VERSION 5.7 ;
BUSBITCHARS "[]" ;
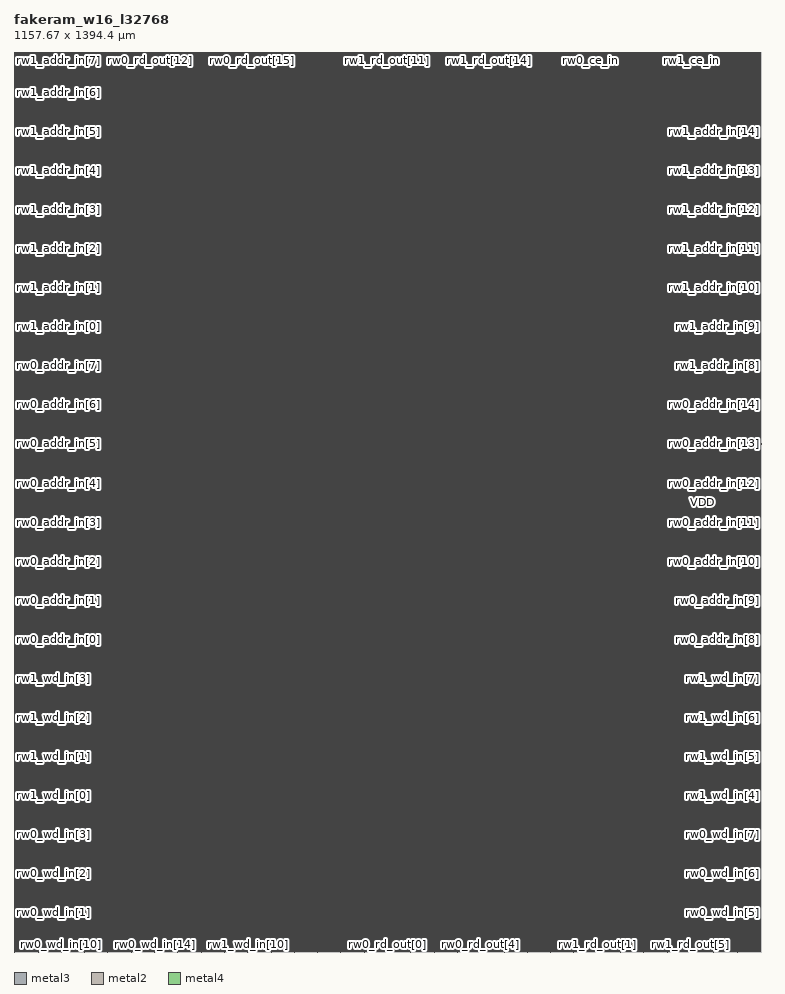
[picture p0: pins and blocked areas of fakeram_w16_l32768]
MACRO fakeram_w16_l32768
  FOREIGN fakeram_w16_l32768 0 0 ;
  SYMMETRY X Y R90 ;
  SIZE 1157.670 BY 1394.400 ;
  CLASS BLOCK ;
  PIN rw0_wd_in[0]
    DIRECTION INPUT ;
    USE SIGNAL ;
    SHAPE ABUTMENT ;
    PORT
      LAYER metal3 ;
      RECT 0.000 0.805 0.210 0.875 ;
    END
  END rw0_wd_in[0]
  PIN rw0_wd_in[1]
    DIRECTION INPUT ;
    USE SIGNAL ;
    SHAPE ABUTMENT ;
    PORT
      LAYER metal3 ;
      RECT 0.000 61.285 0.210 61.355 ;
    END
  END rw0_wd_in[1]
  PIN rw0_wd_in[2]
    DIRECTION INPUT ;
    USE SIGNAL ;
    SHAPE ABUTMENT ;
    PORT
      LAYER metal3 ;
      RECT 0.000 121.765 0.210 121.835 ;
    END
  END rw0_wd_in[2]
  PIN rw0_wd_in[3]
    DIRECTION INPUT ;
    USE SIGNAL ;
    SHAPE ABUTMENT ;
    PORT
      LAYER metal3 ;
      RECT 0.000 182.245 0.210 182.315 ;
    END
  END rw0_wd_in[3]
  PIN rw0_wd_in[4]
    DIRECTION INPUT ;
    USE SIGNAL ;
    SHAPE ABUTMENT ;
    PORT
      LAYER metal3 ;
      RECT 1157.460 0.805 1157.670 0.875 ;
    END
  END rw0_wd_in[4]
  PIN rw0_wd_in[5]
    DIRECTION INPUT ;
    USE SIGNAL ;
    SHAPE ABUTMENT ;
    PORT
      LAYER metal3 ;
      RECT 1157.460 61.285 1157.670 61.355 ;
    END
  END rw0_wd_in[5]
  PIN rw0_wd_in[6]
    DIRECTION INPUT ;
    USE SIGNAL ;
    SHAPE ABUTMENT ;
    PORT
      LAYER metal3 ;
      RECT 1157.460 121.765 1157.670 121.835 ;
    END
  END rw0_wd_in[6]
  PIN rw0_wd_in[7]
    DIRECTION INPUT ;
    USE SIGNAL ;
    SHAPE ABUTMENT ;
    PORT
      LAYER metal3 ;
      RECT 1157.460 182.245 1157.670 182.315 ;
    END
  END rw0_wd_in[7]
  PIN rw0_wd_in[8]
    DIRECTION INPUT ;
    USE SIGNAL ;
    SHAPE ABUTMENT ;
    PORT
      LAYER metal2 ;
      RECT 1.105 0.000 1.175 0.210 ;
    END
  END rw0_wd_in[8]
  PIN rw0_wd_in[9]
    DIRECTION INPUT ;
    USE SIGNAL ;
    SHAPE ABUTMENT ;
    PORT
      LAYER metal2 ;
      RECT 37.205 0.000 37.275 0.210 ;
    END
  END rw0_wd_in[9]
  PIN rw0_wd_in[10]
    DIRECTION INPUT ;
    USE SIGNAL ;
    SHAPE ABUTMENT ;
    PORT
      LAYER metal2 ;
      RECT 73.305 0.000 73.375 0.210 ;
    END
  END rw0_wd_in[10]
  PIN rw0_wd_in[11]
    DIRECTION INPUT ;
    USE SIGNAL ;
    SHAPE ABUTMENT ;
    PORT
      LAYER metal2 ;
      RECT 109.405 0.000 109.475 0.210 ;
    END
  END rw0_wd_in[11]
  PIN rw0_wd_in[12]
    DIRECTION INPUT ;
    USE SIGNAL ;
    SHAPE ABUTMENT ;
    PORT
      LAYER metal2 ;
      RECT 145.505 0.000 145.575 0.210 ;
    END
  END rw0_wd_in[12]
  PIN rw0_wd_in[13]
    DIRECTION INPUT ;
    USE SIGNAL ;
    SHAPE ABUTMENT ;
    PORT
      LAYER metal2 ;
      RECT 181.605 0.000 181.675 0.210 ;
    END
  END rw0_wd_in[13]
  PIN rw0_wd_in[14]
    DIRECTION INPUT ;
    USE SIGNAL ;
    SHAPE ABUTMENT ;
    PORT
      LAYER metal2 ;
      RECT 217.705 0.000 217.775 0.210 ;
    END
  END rw0_wd_in[14]
  PIN rw0_wd_in[15]
    DIRECTION INPUT ;
    USE SIGNAL ;
    SHAPE ABUTMENT ;
    PORT
      LAYER metal2 ;
      RECT 253.805 0.000 253.875 0.210 ;
    END
  END rw0_wd_in[15]
  PIN rw1_wd_in[0]
    DIRECTION INPUT ;
    USE SIGNAL ;
    SHAPE ABUTMENT ;
    PORT
      LAYER metal3 ;
      RECT 0.000 242.725 0.210 242.795 ;
    END
  END rw1_wd_in[0]
  PIN rw1_wd_in[1]
    DIRECTION INPUT ;
    USE SIGNAL ;
    SHAPE ABUTMENT ;
    PORT
      LAYER metal3 ;
      RECT 0.000 303.205 0.210 303.275 ;
    END
  END rw1_wd_in[1]
  PIN rw1_wd_in[2]
    DIRECTION INPUT ;
    USE SIGNAL ;
    SHAPE ABUTMENT ;
    PORT
      LAYER metal3 ;
      RECT 0.000 363.685 0.210 363.755 ;
    END
  END rw1_wd_in[2]
  PIN rw1_wd_in[3]
    DIRECTION INPUT ;
    USE SIGNAL ;
    SHAPE ABUTMENT ;
    PORT
      LAYER metal3 ;
      RECT 0.000 424.165 0.210 424.235 ;
    END
  END rw1_wd_in[3]
  PIN rw1_wd_in[4]
    DIRECTION INPUT ;
    USE SIGNAL ;
    SHAPE ABUTMENT ;
    PORT
      LAYER metal3 ;
      RECT 1157.460 242.725 1157.670 242.795 ;
    END
  END rw1_wd_in[4]
  PIN rw1_wd_in[5]
    DIRECTION INPUT ;
    USE SIGNAL ;
    SHAPE ABUTMENT ;
    PORT
      LAYER metal3 ;
      RECT 1157.460 303.205 1157.670 303.275 ;
    END
  END rw1_wd_in[5]
  PIN rw1_wd_in[6]
    DIRECTION INPUT ;
    USE SIGNAL ;
    SHAPE ABUTMENT ;
    PORT
      LAYER metal3 ;
      RECT 1157.460 363.685 1157.670 363.755 ;
    END
  END rw1_wd_in[6]
  PIN rw1_wd_in[7]
    DIRECTION INPUT ;
    USE SIGNAL ;
    SHAPE ABUTMENT ;
    PORT
      LAYER metal3 ;
      RECT 1157.460 424.165 1157.670 424.235 ;
    END
  END rw1_wd_in[7]
  PIN rw1_wd_in[8]
    DIRECTION INPUT ;
    USE SIGNAL ;
    SHAPE ABUTMENT ;
    PORT
      LAYER metal2 ;
      RECT 289.905 0.000 289.975 0.210 ;
    END
  END rw1_wd_in[8]
  PIN rw1_wd_in[9]
    DIRECTION INPUT ;
    USE SIGNAL ;
    SHAPE ABUTMENT ;
    PORT
      LAYER metal2 ;
      RECT 326.005 0.000 326.075 0.210 ;
    END
  END rw1_wd_in[9]
  PIN rw1_wd_in[10]
    DIRECTION INPUT ;
    USE SIGNAL ;
    SHAPE ABUTMENT ;
    PORT
      LAYER metal2 ;
      RECT 362.105 0.000 362.175 0.210 ;
    END
  END rw1_wd_in[10]
  PIN rw1_wd_in[11]
    DIRECTION INPUT ;
    USE SIGNAL ;
    SHAPE ABUTMENT ;
    PORT
      LAYER metal2 ;
      RECT 398.205 0.000 398.275 0.210 ;
    END
  END rw1_wd_in[11]
  PIN rw1_wd_in[12]
    DIRECTION INPUT ;
    USE SIGNAL ;
    SHAPE ABUTMENT ;
    PORT
      LAYER metal2 ;
      RECT 434.305 0.000 434.375 0.210 ;
    END
  END rw1_wd_in[12]
  PIN rw1_wd_in[13]
    DIRECTION INPUT ;
    USE SIGNAL ;
    SHAPE ABUTMENT ;
    PORT
      LAYER metal2 ;
      RECT 470.405 0.000 470.475 0.210 ;
    END
  END rw1_wd_in[13]
  PIN rw1_wd_in[14]
    DIRECTION INPUT ;
    USE SIGNAL ;
    SHAPE ABUTMENT ;
    PORT
      LAYER metal2 ;
      RECT 506.505 0.000 506.575 0.210 ;
    END
  END rw1_wd_in[14]
  PIN rw1_wd_in[15]
    DIRECTION INPUT ;
    USE SIGNAL ;
    SHAPE ABUTMENT ;
    PORT
      LAYER metal2 ;
      RECT 542.605 0.000 542.675 0.210 ;
    END
  END rw1_wd_in[15]
  PIN rw0_rd_out[0]
    DIRECTION OUTPUT ;
    USE SIGNAL ;
    SHAPE ABUTMENT ;
    PORT
      LAYER metal2 ;
      RECT 578.705 0.000 578.775 0.210 ;
    END
  END rw0_rd_out[0]
  PIN rw0_rd_out[1]
    DIRECTION OUTPUT ;
    USE SIGNAL ;
    SHAPE ABUTMENT ;
    PORT
      LAYER metal2 ;
      RECT 614.805 0.000 614.875 0.210 ;
    END
  END rw0_rd_out[1]
  PIN rw0_rd_out[2]
    DIRECTION OUTPUT ;
    USE SIGNAL ;
    SHAPE ABUTMENT ;
    PORT
      LAYER metal2 ;
      RECT 650.905 0.000 650.975 0.210 ;
    END
  END rw0_rd_out[2]
  PIN rw0_rd_out[3]
    DIRECTION OUTPUT ;
    USE SIGNAL ;
    SHAPE ABUTMENT ;
    PORT
      LAYER metal2 ;
      RECT 687.005 0.000 687.075 0.210 ;
    END
  END rw0_rd_out[3]
  PIN rw0_rd_out[4]
    DIRECTION OUTPUT ;
    USE SIGNAL ;
    SHAPE ABUTMENT ;
    PORT
      LAYER metal2 ;
      RECT 723.105 0.000 723.175 0.210 ;
    END
  END rw0_rd_out[4]
  PIN rw0_rd_out[5]
    DIRECTION OUTPUT ;
    USE SIGNAL ;
    SHAPE ABUTMENT ;
    PORT
      LAYER metal2 ;
      RECT 759.205 0.000 759.275 0.210 ;
    END
  END rw0_rd_out[5]
  PIN rw0_rd_out[6]
    DIRECTION OUTPUT ;
    USE SIGNAL ;
    SHAPE ABUTMENT ;
    PORT
      LAYER metal2 ;
      RECT 795.305 0.000 795.375 0.210 ;
    END
  END rw0_rd_out[6]
  PIN rw0_rd_out[7]
    DIRECTION OUTPUT ;
    USE SIGNAL ;
    SHAPE ABUTMENT ;
    PORT
      LAYER metal2 ;
      RECT 831.405 0.000 831.475 0.210 ;
    END
  END rw0_rd_out[7]
  PIN rw0_rd_out[8]
    DIRECTION OUTPUT ;
    USE SIGNAL ;
    SHAPE ABUTMENT ;
    PORT
      LAYER metal2 ;
      RECT 1.105 1394.190 1.175 1394.400 ;
    END
  END rw0_rd_out[8]
  PIN rw0_rd_out[9]
    DIRECTION OUTPUT ;
    USE SIGNAL ;
    SHAPE ABUTMENT ;
    PORT
      LAYER metal2 ;
      RECT 53.545 1394.190 53.615 1394.400 ;
    END
  END rw0_rd_out[9]
  PIN rw0_rd_out[10]
    DIRECTION OUTPUT ;
    USE SIGNAL ;
    SHAPE ABUTMENT ;
    PORT
      LAYER metal2 ;
      RECT 105.985 1394.190 106.055 1394.400 ;
    END
  END rw0_rd_out[10]
  PIN rw0_rd_out[11]
    DIRECTION OUTPUT ;
    USE SIGNAL ;
    SHAPE ABUTMENT ;
    PORT
      LAYER metal2 ;
      RECT 158.425 1394.190 158.495 1394.400 ;
    END
  END rw0_rd_out[11]
  PIN rw0_rd_out[12]
    DIRECTION OUTPUT ;
    USE SIGNAL ;
    SHAPE ABUTMENT ;
    PORT
      LAYER metal2 ;
      RECT 210.865 1394.190 210.935 1394.400 ;
    END
  END rw0_rd_out[12]
  PIN rw0_rd_out[13]
    DIRECTION OUTPUT ;
    USE SIGNAL ;
    SHAPE ABUTMENT ;
    PORT
      LAYER metal2 ;
      RECT 263.305 1394.190 263.375 1394.400 ;
    END
  END rw0_rd_out[13]
  PIN rw0_rd_out[14]
    DIRECTION OUTPUT ;
    USE SIGNAL ;
    SHAPE ABUTMENT ;
    PORT
      LAYER metal2 ;
      RECT 315.745 1394.190 315.815 1394.400 ;
    END
  END rw0_rd_out[14]
  PIN rw0_rd_out[15]
    DIRECTION OUTPUT ;
    USE SIGNAL ;
    SHAPE ABUTMENT ;
    PORT
      LAYER metal2 ;
      RECT 368.185 1394.190 368.255 1394.400 ;
    END
  END rw0_rd_out[15]
  PIN rw1_rd_out[0]
    DIRECTION OUTPUT ;
    USE SIGNAL ;
    SHAPE ABUTMENT ;
    PORT
      LAYER metal2 ;
      RECT 867.505 0.000 867.575 0.210 ;
    END
  END rw1_rd_out[0]
  PIN rw1_rd_out[1]
    DIRECTION OUTPUT ;
    USE SIGNAL ;
    SHAPE ABUTMENT ;
    PORT
      LAYER metal2 ;
      RECT 903.605 0.000 903.675 0.210 ;
    END
  END rw1_rd_out[1]
  PIN rw1_rd_out[2]
    DIRECTION OUTPUT ;
    USE SIGNAL ;
    SHAPE ABUTMENT ;
    PORT
      LAYER metal2 ;
      RECT 939.705 0.000 939.775 0.210 ;
    END
  END rw1_rd_out[2]
  PIN rw1_rd_out[3]
    DIRECTION OUTPUT ;
    USE SIGNAL ;
    SHAPE ABUTMENT ;
    PORT
      LAYER metal2 ;
      RECT 975.805 0.000 975.875 0.210 ;
    END
  END rw1_rd_out[3]
  PIN rw1_rd_out[4]
    DIRECTION OUTPUT ;
    USE SIGNAL ;
    SHAPE ABUTMENT ;
    PORT
      LAYER metal2 ;
      RECT 1011.905 0.000 1011.975 0.210 ;
    END
  END rw1_rd_out[4]
  PIN rw1_rd_out[5]
    DIRECTION OUTPUT ;
    USE SIGNAL ;
    SHAPE ABUTMENT ;
    PORT
      LAYER metal2 ;
      RECT 1048.005 0.000 1048.075 0.210 ;
    END
  END rw1_rd_out[5]
  PIN rw1_rd_out[6]
    DIRECTION OUTPUT ;
    USE SIGNAL ;
    SHAPE ABUTMENT ;
    PORT
      LAYER metal2 ;
      RECT 1084.105 0.000 1084.175 0.210 ;
    END
  END rw1_rd_out[6]
  PIN rw1_rd_out[7]
    DIRECTION OUTPUT ;
    USE SIGNAL ;
    SHAPE ABUTMENT ;
    PORT
      LAYER metal2 ;
      RECT 1120.205 0.000 1120.275 0.210 ;
    END
  END rw1_rd_out[7]
  PIN rw1_rd_out[8]
    DIRECTION OUTPUT ;
    USE SIGNAL ;
    SHAPE ABUTMENT ;
    PORT
      LAYER metal2 ;
      RECT 420.625 1394.190 420.695 1394.400 ;
    END
  END rw1_rd_out[8]
  PIN rw1_rd_out[9]
    DIRECTION OUTPUT ;
    USE SIGNAL ;
    SHAPE ABUTMENT ;
    PORT
      LAYER metal2 ;
      RECT 473.065 1394.190 473.135 1394.400 ;
    END
  END rw1_rd_out[9]
  PIN rw1_rd_out[10]
    DIRECTION OUTPUT ;
    USE SIGNAL ;
    SHAPE ABUTMENT ;
    PORT
      LAYER metal2 ;
      RECT 525.505 1394.190 525.575 1394.400 ;
    END
  END rw1_rd_out[10]
  PIN rw1_rd_out[11]
    DIRECTION OUTPUT ;
    USE SIGNAL ;
    SHAPE ABUTMENT ;
    PORT
      LAYER metal2 ;
      RECT 577.945 1394.190 578.015 1394.400 ;
    END
  END rw1_rd_out[11]
  PIN rw1_rd_out[12]
    DIRECTION OUTPUT ;
    USE SIGNAL ;
    SHAPE ABUTMENT ;
    PORT
      LAYER metal2 ;
      RECT 630.385 1394.190 630.455 1394.400 ;
    END
  END rw1_rd_out[12]
  PIN rw1_rd_out[13]
    DIRECTION OUTPUT ;
    USE SIGNAL ;
    SHAPE ABUTMENT ;
    PORT
      LAYER metal2 ;
      RECT 682.825 1394.190 682.895 1394.400 ;
    END
  END rw1_rd_out[13]
  PIN rw1_rd_out[14]
    DIRECTION OUTPUT ;
    USE SIGNAL ;
    SHAPE ABUTMENT ;
    PORT
      LAYER metal2 ;
      RECT 735.265 1394.190 735.335 1394.400 ;
    END
  END rw1_rd_out[14]
  PIN rw1_rd_out[15]
    DIRECTION OUTPUT ;
    USE SIGNAL ;
    SHAPE ABUTMENT ;
    PORT
      LAYER metal2 ;
      RECT 787.705 1394.190 787.775 1394.400 ;
    END
  END rw1_rd_out[15]
  PIN rw0_addr_in[0]
    DIRECTION INPUT ;
    USE SIGNAL ;
    SHAPE ABUTMENT ;
    PORT
      LAYER metal3 ;
      RECT 0.000 484.645 0.210 484.715 ;
    END
  END rw0_addr_in[0]
  PIN rw0_addr_in[1]
    DIRECTION INPUT ;
    USE SIGNAL ;
    SHAPE ABUTMENT ;
    PORT
      LAYER metal3 ;
      RECT 0.000 545.125 0.210 545.195 ;
    END
  END rw0_addr_in[1]
  PIN rw0_addr_in[2]
    DIRECTION INPUT ;
    USE SIGNAL ;
    SHAPE ABUTMENT ;
    PORT
      LAYER metal3 ;
      RECT 0.000 605.605 0.210 605.675 ;
    END
  END rw0_addr_in[2]
  PIN rw0_addr_in[3]
    DIRECTION INPUT ;
    USE SIGNAL ;
    SHAPE ABUTMENT ;
    PORT
      LAYER metal3 ;
      RECT 0.000 666.085 0.210 666.155 ;
    END
  END rw0_addr_in[3]
  PIN rw0_addr_in[4]
    DIRECTION INPUT ;
    USE SIGNAL ;
    SHAPE ABUTMENT ;
    PORT
      LAYER metal3 ;
      RECT 0.000 726.565 0.210 726.635 ;
    END
  END rw0_addr_in[4]
  PIN rw0_addr_in[5]
    DIRECTION INPUT ;
    USE SIGNAL ;
    SHAPE ABUTMENT ;
    PORT
      LAYER metal3 ;
      RECT 0.000 787.045 0.210 787.115 ;
    END
  END rw0_addr_in[5]
  PIN rw0_addr_in[6]
    DIRECTION INPUT ;
    USE SIGNAL ;
    SHAPE ABUTMENT ;
    PORT
      LAYER metal3 ;
      RECT 0.000 847.525 0.210 847.595 ;
    END
  END rw0_addr_in[6]
  PIN rw0_addr_in[7]
    DIRECTION INPUT ;
    USE SIGNAL ;
    SHAPE ABUTMENT ;
    PORT
      LAYER metal3 ;
      RECT 0.000 908.005 0.210 908.075 ;
    END
  END rw0_addr_in[7]
  PIN rw0_addr_in[8]
    DIRECTION INPUT ;
    USE SIGNAL ;
    SHAPE ABUTMENT ;
    PORT
      LAYER metal3 ;
      RECT 1157.460 484.645 1157.670 484.715 ;
    END
  END rw0_addr_in[8]
  PIN rw0_addr_in[9]
    DIRECTION INPUT ;
    USE SIGNAL ;
    SHAPE ABUTMENT ;
    PORT
      LAYER metal3 ;
      RECT 1157.460 545.125 1157.670 545.195 ;
    END
  END rw0_addr_in[9]
  PIN rw0_addr_in[10]
    DIRECTION INPUT ;
    USE SIGNAL ;
    SHAPE ABUTMENT ;
    PORT
      LAYER metal3 ;
      RECT 1157.460 605.605 1157.670 605.675 ;
    END
  END rw0_addr_in[10]
  PIN rw0_addr_in[11]
    DIRECTION INPUT ;
    USE SIGNAL ;
    SHAPE ABUTMENT ;
    PORT
      LAYER metal3 ;
      RECT 1157.460 666.085 1157.670 666.155 ;
    END
  END rw0_addr_in[11]
  PIN rw0_addr_in[12]
    DIRECTION INPUT ;
    USE SIGNAL ;
    SHAPE ABUTMENT ;
    PORT
      LAYER metal3 ;
      RECT 1157.460 726.565 1157.670 726.635 ;
    END
  END rw0_addr_in[12]
  PIN rw0_addr_in[13]
    DIRECTION INPUT ;
    USE SIGNAL ;
    SHAPE ABUTMENT ;
    PORT
      LAYER metal3 ;
      RECT 1157.460 787.045 1157.670 787.115 ;
    END
  END rw0_addr_in[13]
  PIN rw0_addr_in[14]
    DIRECTION INPUT ;
    USE SIGNAL ;
    SHAPE ABUTMENT ;
    PORT
      LAYER metal3 ;
      RECT 1157.460 847.525 1157.670 847.595 ;
    END
  END rw0_addr_in[14]
  PIN rw1_addr_in[0]
    DIRECTION INPUT ;
    USE SIGNAL ;
    SHAPE ABUTMENT ;
    PORT
      LAYER metal3 ;
      RECT 0.000 968.485 0.210 968.555 ;
    END
  END rw1_addr_in[0]
  PIN rw1_addr_in[1]
    DIRECTION INPUT ;
    USE SIGNAL ;
    SHAPE ABUTMENT ;
    PORT
      LAYER metal3 ;
      RECT 0.000 1028.965 0.210 1029.035 ;
    END
  END rw1_addr_in[1]
  PIN rw1_addr_in[2]
    DIRECTION INPUT ;
    USE SIGNAL ;
    SHAPE ABUTMENT ;
    PORT
      LAYER metal3 ;
      RECT 0.000 1089.445 0.210 1089.515 ;
    END
  END rw1_addr_in[2]
  PIN rw1_addr_in[3]
    DIRECTION INPUT ;
    USE SIGNAL ;
    SHAPE ABUTMENT ;
    PORT
      LAYER metal3 ;
      RECT 0.000 1149.925 0.210 1149.995 ;
    END
  END rw1_addr_in[3]
  PIN rw1_addr_in[4]
    DIRECTION INPUT ;
    USE SIGNAL ;
    SHAPE ABUTMENT ;
    PORT
      LAYER metal3 ;
      RECT 0.000 1210.405 0.210 1210.475 ;
    END
  END rw1_addr_in[4]
  PIN rw1_addr_in[5]
    DIRECTION INPUT ;
    USE SIGNAL ;
    SHAPE ABUTMENT ;
    PORT
      LAYER metal3 ;
      RECT 0.000 1270.885 0.210 1270.955 ;
    END
  END rw1_addr_in[5]
  PIN rw1_addr_in[6]
    DIRECTION INPUT ;
    USE SIGNAL ;
    SHAPE ABUTMENT ;
    PORT
      LAYER metal3 ;
      RECT 0.000 1331.365 0.210 1331.435 ;
    END
  END rw1_addr_in[6]
  PIN rw1_addr_in[7]
    DIRECTION INPUT ;
    USE SIGNAL ;
    SHAPE ABUTMENT ;
    PORT
      LAYER metal3 ;
      RECT 0.000 1391.845 0.210 1391.915 ;
    END
  END rw1_addr_in[7]
  PIN rw1_addr_in[8]
    DIRECTION INPUT ;
    USE SIGNAL ;
    SHAPE ABUTMENT ;
    PORT
      LAYER metal3 ;
      RECT 1157.460 908.005 1157.670 908.075 ;
    END
  END rw1_addr_in[8]
  PIN rw1_addr_in[9]
    DIRECTION INPUT ;
    USE SIGNAL ;
    SHAPE ABUTMENT ;
    PORT
      LAYER metal3 ;
      RECT 1157.460 968.485 1157.670 968.555 ;
    END
  END rw1_addr_in[9]
  PIN rw1_addr_in[10]
    DIRECTION INPUT ;
    USE SIGNAL ;
    SHAPE ABUTMENT ;
    PORT
      LAYER metal3 ;
      RECT 1157.460 1028.965 1157.670 1029.035 ;
    END
  END rw1_addr_in[10]
  PIN rw1_addr_in[11]
    DIRECTION INPUT ;
    USE SIGNAL ;
    SHAPE ABUTMENT ;
    PORT
      LAYER metal3 ;
      RECT 1157.460 1089.445 1157.670 1089.515 ;
    END
  END rw1_addr_in[11]
  PIN rw1_addr_in[12]
    DIRECTION INPUT ;
    USE SIGNAL ;
    SHAPE ABUTMENT ;
    PORT
      LAYER metal3 ;
      RECT 1157.460 1149.925 1157.670 1149.995 ;
    END
  END rw1_addr_in[12]
  PIN rw1_addr_in[13]
    DIRECTION INPUT ;
    USE SIGNAL ;
    SHAPE ABUTMENT ;
    PORT
      LAYER metal3 ;
      RECT 1157.460 1210.405 1157.670 1210.475 ;
    END
  END rw1_addr_in[13]
  PIN rw1_addr_in[14]
    DIRECTION INPUT ;
    USE SIGNAL ;
    SHAPE ABUTMENT ;
    PORT
      LAYER metal3 ;
      RECT 1157.460 1270.885 1157.670 1270.955 ;
    END
  END rw1_addr_in[14]
  PIN rw0_we_in
    DIRECTION INPUT ;
    USE SIGNAL ;
    SHAPE ABUTMENT ;
    PORT
      LAYER metal2 ;
      RECT 840.145 1394.190 840.215 1394.400 ;
    END
  END rw0_we_in
  PIN rw0_ce_in
    DIRECTION INPUT ;
    USE SIGNAL ;
    SHAPE ABUTMENT ;
    PORT
      LAYER metal2 ;
      RECT 892.585 1394.190 892.655 1394.400 ;
    END
  END rw0_ce_in
  PIN rw0_clk
    DIRECTION INPUT ;
    USE SIGNAL ;
    SHAPE ABUTMENT ;
    PORT
      LAYER metal2 ;
      RECT 945.025 1394.190 945.095 1394.400 ;
    END
  END rw0_clk
  PIN rw1_we_in
    DIRECTION INPUT ;
    USE SIGNAL ;
    SHAPE ABUTMENT ;
    PORT
      LAYER metal2 ;
      RECT 997.465 1394.190 997.535 1394.400 ;
    END
  END rw1_we_in
  PIN rw1_ce_in
    DIRECTION INPUT ;
    USE SIGNAL ;
    SHAPE ABUTMENT ;
    PORT
      LAYER metal2 ;
      RECT 1049.905 1394.190 1049.975 1394.400 ;
    END
  END rw1_ce_in
  PIN rw1_clk
    DIRECTION INPUT ;
    USE SIGNAL ;
    SHAPE ABUTMENT ;
    PORT
      LAYER metal2 ;
      RECT 1102.345 1394.190 1102.415 1394.400 ;
    END
  END rw1_clk
  PIN VSS
    DIRECTION INOUT ;
    USE GROUND ;
    PORT
      LAYER metal4 ;
      RECT 1.000 0.840 1.280 1393.560 ;
      RECT 3.240 0.840 3.520 1393.560 ;
      RECT 5.480 0.840 5.760 1393.560 ;
      RECT 7.720 0.840 8.000 1393.560 ;
      RECT 9.960 0.840 10.240 1393.560 ;
      RECT 12.200 0.840 12.480 1393.560 ;
      RECT 14.440 0.840 14.720 1393.560 ;
      RECT 16.680 0.840 16.960 1393.560 ;
      RECT 18.920 0.840 19.200 1393.560 ;
      RECT 21.160 0.840 21.440 1393.560 ;
      RECT 23.400 0.840 23.680 1393.560 ;
      RECT 25.640 0.840 25.920 1393.560 ;
      RECT 27.880 0.840 28.160 1393.560 ;
      RECT 30.120 0.840 30.400 1393.560 ;
      RECT 32.360 0.840 32.640 1393.560 ;
      RECT 34.600 0.840 34.880 1393.560 ;
      RECT 36.840 0.840 37.120 1393.560 ;
      RECT 39.080 0.840 39.360 1393.560 ;
      RECT 41.320 0.840 41.600 1393.560 ;
      RECT 43.560 0.840 43.840 1393.560 ;
      RECT 45.800 0.840 46.080 1393.560 ;
      RECT 48.040 0.840 48.320 1393.560 ;
      RECT 50.280 0.840 50.560 1393.560 ;
      RECT 52.520 0.840 52.800 1393.560 ;
      RECT 54.760 0.840 55.040 1393.560 ;
      RECT 57.000 0.840 57.280 1393.560 ;
      RECT 59.240 0.840 59.520 1393.560 ;
      RECT 61.480 0.840 61.760 1393.560 ;
      RECT 63.720 0.840 64.000 1393.560 ;
      RECT 65.960 0.840 66.240 1393.560 ;
      RECT 68.200 0.840 68.480 1393.560 ;
      RECT 70.440 0.840 70.720 1393.560 ;
      RECT 72.680 0.840 72.960 1393.560 ;
      RECT 74.920 0.840 75.200 1393.560 ;
      RECT 77.160 0.840 77.440 1393.560 ;
      RECT 79.400 0.840 79.680 1393.560 ;
      RECT 81.640 0.840 81.920 1393.560 ;
      RECT 83.880 0.840 84.160 1393.560 ;
      RECT 86.120 0.840 86.400 1393.560 ;
      RECT 88.360 0.840 88.640 1393.560 ;
      RECT 90.600 0.840 90.880 1393.560 ;
      RECT 92.840 0.840 93.120 1393.560 ;
      RECT 95.080 0.840 95.360 1393.560 ;
      RECT 97.320 0.840 97.600 1393.560 ;
      RECT 99.560 0.840 99.840 1393.560 ;
      RECT 101.800 0.840 102.080 1393.560 ;
      RECT 104.040 0.840 104.320 1393.560 ;
      RECT 106.280 0.840 106.560 1393.560 ;
      RECT 108.520 0.840 108.800 1393.560 ;
      RECT 110.760 0.840 111.040 1393.560 ;
      RECT 113.000 0.840 113.280 1393.560 ;
      RECT 115.240 0.840 115.520 1393.560 ;
      RECT 117.480 0.840 117.760 1393.560 ;
      RECT 119.720 0.840 120.000 1393.560 ;
      RECT 121.960 0.840 122.240 1393.560 ;
      RECT 124.200 0.840 124.480 1393.560 ;
      RECT 126.440 0.840 126.720 1393.560 ;
      RECT 128.680 0.840 128.960 1393.560 ;
      RECT 130.920 0.840 131.200 1393.560 ;
      RECT 133.160 0.840 133.440 1393.560 ;
      RECT 135.400 0.840 135.680 1393.560 ;
      RECT 137.640 0.840 137.920 1393.560 ;
      RECT 139.880 0.840 140.160 1393.560 ;
      RECT 142.120 0.840 142.400 1393.560 ;
      RECT 144.360 0.840 144.640 1393.560 ;
      RECT 146.600 0.840 146.880 1393.560 ;
      RECT 148.840 0.840 149.120 1393.560 ;
      RECT 151.080 0.840 151.360 1393.560 ;
      RECT 153.320 0.840 153.600 1393.560 ;
      RECT 155.560 0.840 155.840 1393.560 ;
      RECT 157.800 0.840 158.080 1393.560 ;
      RECT 160.040 0.840 160.320 1393.560 ;
      RECT 162.280 0.840 162.560 1393.560 ;
      RECT 164.520 0.840 164.800 1393.560 ;
      RECT 166.760 0.840 167.040 1393.560 ;
      RECT 169.000 0.840 169.280 1393.560 ;
      RECT 171.240 0.840 171.520 1393.560 ;
      RECT 173.480 0.840 173.760 1393.560 ;
      RECT 175.720 0.840 176.000 1393.560 ;
      RECT 177.960 0.840 178.240 1393.560 ;
      RECT 180.200 0.840 180.480 1393.560 ;
      RECT 182.440 0.840 182.720 1393.560 ;
      RECT 184.680 0.840 184.960 1393.560 ;
      RECT 186.920 0.840 187.200 1393.560 ;
      RECT 189.160 0.840 189.440 1393.560 ;
      RECT 191.400 0.840 191.680 1393.560 ;
      RECT 193.640 0.840 193.920 1393.560 ;
      RECT 195.880 0.840 196.160 1393.560 ;
      RECT 198.120 0.840 198.400 1393.560 ;
      RECT 200.360 0.840 200.640 1393.560 ;
      RECT 202.600 0.840 202.880 1393.560 ;
      RECT 204.840 0.840 205.120 1393.560 ;
      RECT 207.080 0.840 207.360 1393.560 ;
      RECT 209.320 0.840 209.600 1393.560 ;
      RECT 211.560 0.840 211.840 1393.560 ;
      RECT 213.800 0.840 214.080 1393.560 ;
      RECT 216.040 0.840 216.320 1393.560 ;
      RECT 218.280 0.840 218.560 1393.560 ;
      RECT 220.520 0.840 220.800 1393.560 ;
      RECT 222.760 0.840 223.040 1393.560 ;
      RECT 225.000 0.840 225.280 1393.560 ;
      RECT 227.240 0.840 227.520 1393.560 ;
      RECT 229.480 0.840 229.760 1393.560 ;
      RECT 231.720 0.840 232.000 1393.560 ;
      RECT 233.960 0.840 234.240 1393.560 ;
      RECT 236.200 0.840 236.480 1393.560 ;
      RECT 238.440 0.840 238.720 1393.560 ;
      RECT 240.680 0.840 240.960 1393.560 ;
      RECT 242.920 0.840 243.200 1393.560 ;
      RECT 245.160 0.840 245.440 1393.560 ;
      RECT 247.400 0.840 247.680 1393.560 ;
      RECT 249.640 0.840 249.920 1393.560 ;
      RECT 251.880 0.840 252.160 1393.560 ;
      RECT 254.120 0.840 254.400 1393.560 ;
      RECT 256.360 0.840 256.640 1393.560 ;
      RECT 258.600 0.840 258.880 1393.560 ;
      RECT 260.840 0.840 261.120 1393.560 ;
      RECT 263.080 0.840 263.360 1393.560 ;
      RECT 265.320 0.840 265.600 1393.560 ;
      RECT 267.560 0.840 267.840 1393.560 ;
      RECT 269.800 0.840 270.080 1393.560 ;
      RECT 272.040 0.840 272.320 1393.560 ;
      RECT 274.280 0.840 274.560 1393.560 ;
      RECT 276.520 0.840 276.800 1393.560 ;
      RECT 278.760 0.840 279.040 1393.560 ;
      RECT 281.000 0.840 281.280 1393.560 ;
      RECT 283.240 0.840 283.520 1393.560 ;
      RECT 285.480 0.840 285.760 1393.560 ;
      RECT 287.720 0.840 288.000 1393.560 ;
      RECT 289.960 0.840 290.240 1393.560 ;
      RECT 292.200 0.840 292.480 1393.560 ;
      RECT 294.440 0.840 294.720 1393.560 ;
      RECT 296.680 0.840 296.960 1393.560 ;
      RECT 298.920 0.840 299.200 1393.560 ;
      RECT 301.160 0.840 301.440 1393.560 ;
      RECT 303.400 0.840 303.680 1393.560 ;
      RECT 305.640 0.840 305.920 1393.560 ;
      RECT 307.880 0.840 308.160 1393.560 ;
      RECT 310.120 0.840 310.400 1393.560 ;
      RECT 312.360 0.840 312.640 1393.560 ;
      RECT 314.600 0.840 314.880 1393.560 ;
      RECT 316.840 0.840 317.120 1393.560 ;
      RECT 319.080 0.840 319.360 1393.560 ;
      RECT 321.320 0.840 321.600 1393.560 ;
      RECT 323.560 0.840 323.840 1393.560 ;
      RECT 325.800 0.840 326.080 1393.560 ;
      RECT 328.040 0.840 328.320 1393.560 ;
      RECT 330.280 0.840 330.560 1393.560 ;
      RECT 332.520 0.840 332.800 1393.560 ;
      RECT 334.760 0.840 335.040 1393.560 ;
      RECT 337.000 0.840 337.280 1393.560 ;
      RECT 339.240 0.840 339.520 1393.560 ;
      RECT 341.480 0.840 341.760 1393.560 ;
      RECT 343.720 0.840 344.000 1393.560 ;
      RECT 345.960 0.840 346.240 1393.560 ;
      RECT 348.200 0.840 348.480 1393.560 ;
      RECT 350.440 0.840 350.720 1393.560 ;
      RECT 352.680 0.840 352.960 1393.560 ;
      RECT 354.920 0.840 355.200 1393.560 ;
      RECT 357.160 0.840 357.440 1393.560 ;
      RECT 359.400 0.840 359.680 1393.560 ;
      RECT 361.640 0.840 361.920 1393.560 ;
      RECT 363.880 0.840 364.160 1393.560 ;
      RECT 366.120 0.840 366.400 1393.560 ;
      RECT 368.360 0.840 368.640 1393.560 ;
      RECT 370.600 0.840 370.880 1393.560 ;
      RECT 372.840 0.840 373.120 1393.560 ;
      RECT 375.080 0.840 375.360 1393.560 ;
      RECT 377.320 0.840 377.600 1393.560 ;
      RECT 379.560 0.840 379.840 1393.560 ;
      RECT 381.800 0.840 382.080 1393.560 ;
      RECT 384.040 0.840 384.320 1393.560 ;
      RECT 386.280 0.840 386.560 1393.560 ;
      RECT 388.520 0.840 388.800 1393.560 ;
      RECT 390.760 0.840 391.040 1393.560 ;
      RECT 393.000 0.840 393.280 1393.560 ;
      RECT 395.240 0.840 395.520 1393.560 ;
      RECT 397.480 0.840 397.760 1393.560 ;
      RECT 399.720 0.840 400.000 1393.560 ;
      RECT 401.960 0.840 402.240 1393.560 ;
      RECT 404.200 0.840 404.480 1393.560 ;
      RECT 406.440 0.840 406.720 1393.560 ;
      RECT 408.680 0.840 408.960 1393.560 ;
      RECT 410.920 0.840 411.200 1393.560 ;
      RECT 413.160 0.840 413.440 1393.560 ;
      RECT 415.400 0.840 415.680 1393.560 ;
      RECT 417.640 0.840 417.920 1393.560 ;
      RECT 419.880 0.840 420.160 1393.560 ;
      RECT 422.120 0.840 422.400 1393.560 ;
      RECT 424.360 0.840 424.640 1393.560 ;
      RECT 426.600 0.840 426.880 1393.560 ;
      RECT 428.840 0.840 429.120 1393.560 ;
      RECT 431.080 0.840 431.360 1393.560 ;
      RECT 433.320 0.840 433.600 1393.560 ;
      RECT 435.560 0.840 435.840 1393.560 ;
      RECT 437.800 0.840 438.080 1393.560 ;
      RECT 440.040 0.840 440.320 1393.560 ;
      RECT 442.280 0.840 442.560 1393.560 ;
      RECT 444.520 0.840 444.800 1393.560 ;
      RECT 446.760 0.840 447.040 1393.560 ;
      RECT 449.000 0.840 449.280 1393.560 ;
      RECT 451.240 0.840 451.520 1393.560 ;
      RECT 453.480 0.840 453.760 1393.560 ;
      RECT 455.720 0.840 456.000 1393.560 ;
      RECT 457.960 0.840 458.240 1393.560 ;
      RECT 460.200 0.840 460.480 1393.560 ;
      RECT 462.440 0.840 462.720 1393.560 ;
      RECT 464.680 0.840 464.960 1393.560 ;
      RECT 466.920 0.840 467.200 1393.560 ;
      RECT 469.160 0.840 469.440 1393.560 ;
      RECT 471.400 0.840 471.680 1393.560 ;
      RECT 473.640 0.840 473.920 1393.560 ;
      RECT 475.880 0.840 476.160 1393.560 ;
      RECT 478.120 0.840 478.400 1393.560 ;
      RECT 480.360 0.840 480.640 1393.560 ;
      RECT 482.600 0.840 482.880 1393.560 ;
      RECT 484.840 0.840 485.120 1393.560 ;
      RECT 487.080 0.840 487.360 1393.560 ;
      RECT 489.320 0.840 489.600 1393.560 ;
      RECT 491.560 0.840 491.840 1393.560 ;
      RECT 493.800 0.840 494.080 1393.560 ;
      RECT 496.040 0.840 496.320 1393.560 ;
      RECT 498.280 0.840 498.560 1393.560 ;
      RECT 500.520 0.840 500.800 1393.560 ;
      RECT 502.760 0.840 503.040 1393.560 ;
      RECT 505.000 0.840 505.280 1393.560 ;
      RECT 507.240 0.840 507.520 1393.560 ;
      RECT 509.480 0.840 509.760 1393.560 ;
      RECT 511.720 0.840 512.000 1393.560 ;
      RECT 513.960 0.840 514.240 1393.560 ;
      RECT 516.200 0.840 516.480 1393.560 ;
      RECT 518.440 0.840 518.720 1393.560 ;
      RECT 520.680 0.840 520.960 1393.560 ;
      RECT 522.920 0.840 523.200 1393.560 ;
      RECT 525.160 0.840 525.440 1393.560 ;
      RECT 527.400 0.840 527.680 1393.560 ;
      RECT 529.640 0.840 529.920 1393.560 ;
      RECT 531.880 0.840 532.160 1393.560 ;
      RECT 534.120 0.840 534.400 1393.560 ;
      RECT 536.360 0.840 536.640 1393.560 ;
      RECT 538.600 0.840 538.880 1393.560 ;
      RECT 540.840 0.840 541.120 1393.560 ;
      RECT 543.080 0.840 543.360 1393.560 ;
      RECT 545.320 0.840 545.600 1393.560 ;
      RECT 547.560 0.840 547.840 1393.560 ;
      RECT 549.800 0.840 550.080 1393.560 ;
      RECT 552.040 0.840 552.320 1393.560 ;
      RECT 554.280 0.840 554.560 1393.560 ;
      RECT 556.520 0.840 556.800 1393.560 ;
      RECT 558.760 0.840 559.040 1393.560 ;
      RECT 561.000 0.840 561.280 1393.560 ;
      RECT 563.240 0.840 563.520 1393.560 ;
      RECT 565.480 0.840 565.760 1393.560 ;
      RECT 567.720 0.840 568.000 1393.560 ;
      RECT 569.960 0.840 570.240 1393.560 ;
      RECT 572.200 0.840 572.480 1393.560 ;
      RECT 574.440 0.840 574.720 1393.560 ;
      RECT 576.680 0.840 576.960 1393.560 ;
      RECT 578.920 0.840 579.200 1393.560 ;
      RECT 581.160 0.840 581.440 1393.560 ;
      RECT 583.400 0.840 583.680 1393.560 ;
      RECT 585.640 0.840 585.920 1393.560 ;
      RECT 587.880 0.840 588.160 1393.560 ;
      RECT 590.120 0.840 590.400 1393.560 ;
      RECT 592.360 0.840 592.640 1393.560 ;
      RECT 594.600 0.840 594.880 1393.560 ;
      RECT 596.840 0.840 597.120 1393.560 ;
      RECT 599.080 0.840 599.360 1393.560 ;
      RECT 601.320 0.840 601.600 1393.560 ;
      RECT 603.560 0.840 603.840 1393.560 ;
      RECT 605.800 0.840 606.080 1393.560 ;
      RECT 608.040 0.840 608.320 1393.560 ;
      RECT 610.280 0.840 610.560 1393.560 ;
      RECT 612.520 0.840 612.800 1393.560 ;
      RECT 614.760 0.840 615.040 1393.560 ;
      RECT 617.000 0.840 617.280 1393.560 ;
      RECT 619.240 0.840 619.520 1393.560 ;
      RECT 621.480 0.840 621.760 1393.560 ;
      RECT 623.720 0.840 624.000 1393.560 ;
      RECT 625.960 0.840 626.240 1393.560 ;
      RECT 628.200 0.840 628.480 1393.560 ;
      RECT 630.440 0.840 630.720 1393.560 ;
      RECT 632.680 0.840 632.960 1393.560 ;
      RECT 634.920 0.840 635.200 1393.560 ;
      RECT 637.160 0.840 637.440 1393.560 ;
      RECT 639.400 0.840 639.680 1393.560 ;
      RECT 641.640 0.840 641.920 1393.560 ;
      RECT 643.880 0.840 644.160 1393.560 ;
      RECT 646.120 0.840 646.400 1393.560 ;
      RECT 648.360 0.840 648.640 1393.560 ;
      RECT 650.600 0.840 650.880 1393.560 ;
      RECT 652.840 0.840 653.120 1393.560 ;
      RECT 655.080 0.840 655.360 1393.560 ;
      RECT 657.320 0.840 657.600 1393.560 ;
      RECT 659.560 0.840 659.840 1393.560 ;
      RECT 661.800 0.840 662.080 1393.560 ;
      RECT 664.040 0.840 664.320 1393.560 ;
      RECT 666.280 0.840 666.560 1393.560 ;
      RECT 668.520 0.840 668.800 1393.560 ;
      RECT 670.760 0.840 671.040 1393.560 ;
      RECT 673.000 0.840 673.280 1393.560 ;
      RECT 675.240 0.840 675.520 1393.560 ;
      RECT 677.480 0.840 677.760 1393.560 ;
      RECT 679.720 0.840 680.000 1393.560 ;
      RECT 681.960 0.840 682.240 1393.560 ;
      RECT 684.200 0.840 684.480 1393.560 ;
      RECT 686.440 0.840 686.720 1393.560 ;
      RECT 688.680 0.840 688.960 1393.560 ;
      RECT 690.920 0.840 691.200 1393.560 ;
      RECT 693.160 0.840 693.440 1393.560 ;
      RECT 695.400 0.840 695.680 1393.560 ;
      RECT 697.640 0.840 697.920 1393.560 ;
      RECT 699.880 0.840 700.160 1393.560 ;
      RECT 702.120 0.840 702.400 1393.560 ;
      RECT 704.360 0.840 704.640 1393.560 ;
      RECT 706.600 0.840 706.880 1393.560 ;
      RECT 708.840 0.840 709.120 1393.560 ;
      RECT 711.080 0.840 711.360 1393.560 ;
      RECT 713.320 0.840 713.600 1393.560 ;
      RECT 715.560 0.840 715.840 1393.560 ;
      RECT 717.800 0.840 718.080 1393.560 ;
      RECT 720.040 0.840 720.320 1393.560 ;
      RECT 722.280 0.840 722.560 1393.560 ;
      RECT 724.520 0.840 724.800 1393.560 ;
      RECT 726.760 0.840 727.040 1393.560 ;
      RECT 729.000 0.840 729.280 1393.560 ;
      RECT 731.240 0.840 731.520 1393.560 ;
      RECT 733.480 0.840 733.760 1393.560 ;
      RECT 735.720 0.840 736.000 1393.560 ;
      RECT 737.960 0.840 738.240 1393.560 ;
      RECT 740.200 0.840 740.480 1393.560 ;
      RECT 742.440 0.840 742.720 1393.560 ;
      RECT 744.680 0.840 744.960 1393.560 ;
      RECT 746.920 0.840 747.200 1393.560 ;
      RECT 749.160 0.840 749.440 1393.560 ;
      RECT 751.400 0.840 751.680 1393.560 ;
      RECT 753.640 0.840 753.920 1393.560 ;
      RECT 755.880 0.840 756.160 1393.560 ;
      RECT 758.120 0.840 758.400 1393.560 ;
      RECT 760.360 0.840 760.640 1393.560 ;
      RECT 762.600 0.840 762.880 1393.560 ;
      RECT 764.840 0.840 765.120 1393.560 ;
      RECT 767.080 0.840 767.360 1393.560 ;
      RECT 769.320 0.840 769.600 1393.560 ;
      RECT 771.560 0.840 771.840 1393.560 ;
      RECT 773.800 0.840 774.080 1393.560 ;
      RECT 776.040 0.840 776.320 1393.560 ;
      RECT 778.280 0.840 778.560 1393.560 ;
      RECT 780.520 0.840 780.800 1393.560 ;
      RECT 782.760 0.840 783.040 1393.560 ;
      RECT 785.000 0.840 785.280 1393.560 ;
      RECT 787.240 0.840 787.520 1393.560 ;
      RECT 789.480 0.840 789.760 1393.560 ;
      RECT 791.720 0.840 792.000 1393.560 ;
      RECT 793.960 0.840 794.240 1393.560 ;
      RECT 796.200 0.840 796.480 1393.560 ;
      RECT 798.440 0.840 798.720 1393.560 ;
      RECT 800.680 0.840 800.960 1393.560 ;
      RECT 802.920 0.840 803.200 1393.560 ;
      RECT 805.160 0.840 805.440 1393.560 ;
      RECT 807.400 0.840 807.680 1393.560 ;
      RECT 809.640 0.840 809.920 1393.560 ;
      RECT 811.880 0.840 812.160 1393.560 ;
      RECT 814.120 0.840 814.400 1393.560 ;
      RECT 816.360 0.840 816.640 1393.560 ;
      RECT 818.600 0.840 818.880 1393.560 ;
      RECT 820.840 0.840 821.120 1393.560 ;
      RECT 823.080 0.840 823.360 1393.560 ;
      RECT 825.320 0.840 825.600 1393.560 ;
      RECT 827.560 0.840 827.840 1393.560 ;
      RECT 829.800 0.840 830.080 1393.560 ;
      RECT 832.040 0.840 832.320 1393.560 ;
      RECT 834.280 0.840 834.560 1393.560 ;
      RECT 836.520 0.840 836.800 1393.560 ;
      RECT 838.760 0.840 839.040 1393.560 ;
      RECT 841.000 0.840 841.280 1393.560 ;
      RECT 843.240 0.840 843.520 1393.560 ;
      RECT 845.480 0.840 845.760 1393.560 ;
      RECT 847.720 0.840 848.000 1393.560 ;
      RECT 849.960 0.840 850.240 1393.560 ;
      RECT 852.200 0.840 852.480 1393.560 ;
      RECT 854.440 0.840 854.720 1393.560 ;
      RECT 856.680 0.840 856.960 1393.560 ;
      RECT 858.920 0.840 859.200 1393.560 ;
      RECT 861.160 0.840 861.440 1393.560 ;
      RECT 863.400 0.840 863.680 1393.560 ;
      RECT 865.640 0.840 865.920 1393.560 ;
      RECT 867.880 0.840 868.160 1393.560 ;
      RECT 870.120 0.840 870.400 1393.560 ;
      RECT 872.360 0.840 872.640 1393.560 ;
      RECT 874.600 0.840 874.880 1393.560 ;
      RECT 876.840 0.840 877.120 1393.560 ;
      RECT 879.080 0.840 879.360 1393.560 ;
      RECT 881.320 0.840 881.600 1393.560 ;
      RECT 883.560 0.840 883.840 1393.560 ;
      RECT 885.800 0.840 886.080 1393.560 ;
      RECT 888.040 0.840 888.320 1393.560 ;
      RECT 890.280 0.840 890.560 1393.560 ;
      RECT 892.520 0.840 892.800 1393.560 ;
      RECT 894.760 0.840 895.040 1393.560 ;
      RECT 897.000 0.840 897.280 1393.560 ;
      RECT 899.240 0.840 899.520 1393.560 ;
      RECT 901.480 0.840 901.760 1393.560 ;
      RECT 903.720 0.840 904.000 1393.560 ;
      RECT 905.960 0.840 906.240 1393.560 ;
      RECT 908.200 0.840 908.480 1393.560 ;
      RECT 910.440 0.840 910.720 1393.560 ;
      RECT 912.680 0.840 912.960 1393.560 ;
      RECT 914.920 0.840 915.200 1393.560 ;
      RECT 917.160 0.840 917.440 1393.560 ;
      RECT 919.400 0.840 919.680 1393.560 ;
      RECT 921.640 0.840 921.920 1393.560 ;
      RECT 923.880 0.840 924.160 1393.560 ;
      RECT 926.120 0.840 926.400 1393.560 ;
      RECT 928.360 0.840 928.640 1393.560 ;
      RECT 930.600 0.840 930.880 1393.560 ;
      RECT 932.840 0.840 933.120 1393.560 ;
      RECT 935.080 0.840 935.360 1393.560 ;
      RECT 937.320 0.840 937.600 1393.560 ;
      RECT 939.560 0.840 939.840 1393.560 ;
      RECT 941.800 0.840 942.080 1393.560 ;
      RECT 944.040 0.840 944.320 1393.560 ;
      RECT 946.280 0.840 946.560 1393.560 ;
      RECT 948.520 0.840 948.800 1393.560 ;
      RECT 950.760 0.840 951.040 1393.560 ;
      RECT 953.000 0.840 953.280 1393.560 ;
      RECT 955.240 0.840 955.520 1393.560 ;
      RECT 957.480 0.840 957.760 1393.560 ;
      RECT 959.720 0.840 960.000 1393.560 ;
      RECT 961.960 0.840 962.240 1393.560 ;
      RECT 964.200 0.840 964.480 1393.560 ;
      RECT 966.440 0.840 966.720 1393.560 ;
      RECT 968.680 0.840 968.960 1393.560 ;
      RECT 970.920 0.840 971.200 1393.560 ;
      RECT 973.160 0.840 973.440 1393.560 ;
      RECT 975.400 0.840 975.680 1393.560 ;
      RECT 977.640 0.840 977.920 1393.560 ;
      RECT 979.880 0.840 980.160 1393.560 ;
      RECT 982.120 0.840 982.400 1393.560 ;
      RECT 984.360 0.840 984.640 1393.560 ;
      RECT 986.600 0.840 986.880 1393.560 ;
      RECT 988.840 0.840 989.120 1393.560 ;
      RECT 991.080 0.840 991.360 1393.560 ;
      RECT 993.320 0.840 993.600 1393.560 ;
      RECT 995.560 0.840 995.840 1393.560 ;
      RECT 997.800 0.840 998.080 1393.560 ;
      RECT 1000.040 0.840 1000.320 1393.560 ;
      RECT 1002.280 0.840 1002.560 1393.560 ;
      RECT 1004.520 0.840 1004.800 1393.560 ;
      RECT 1006.760 0.840 1007.040 1393.560 ;
      RECT 1009.000 0.840 1009.280 1393.560 ;
      RECT 1011.240 0.840 1011.520 1393.560 ;
      RECT 1013.480 0.840 1013.760 1393.560 ;
      RECT 1015.720 0.840 1016.000 1393.560 ;
      RECT 1017.960 0.840 1018.240 1393.560 ;
      RECT 1020.200 0.840 1020.480 1393.560 ;
      RECT 1022.440 0.840 1022.720 1393.560 ;
      RECT 1024.680 0.840 1024.960 1393.560 ;
      RECT 1026.920 0.840 1027.200 1393.560 ;
      RECT 1029.160 0.840 1029.440 1393.560 ;
      RECT 1031.400 0.840 1031.680 1393.560 ;
      RECT 1033.640 0.840 1033.920 1393.560 ;
      RECT 1035.880 0.840 1036.160 1393.560 ;
      RECT 1038.120 0.840 1038.400 1393.560 ;
      RECT 1040.360 0.840 1040.640 1393.560 ;
      RECT 1042.600 0.840 1042.880 1393.560 ;
      RECT 1044.840 0.840 1045.120 1393.560 ;
      RECT 1047.080 0.840 1047.360 1393.560 ;
      RECT 1049.320 0.840 1049.600 1393.560 ;
      RECT 1051.560 0.840 1051.840 1393.560 ;
      RECT 1053.800 0.840 1054.080 1393.560 ;
      RECT 1056.040 0.840 1056.320 1393.560 ;
      RECT 1058.280 0.840 1058.560 1393.560 ;
      RECT 1060.520 0.840 1060.800 1393.560 ;
      RECT 1062.760 0.840 1063.040 1393.560 ;
      RECT 1065.000 0.840 1065.280 1393.560 ;
      RECT 1067.240 0.840 1067.520 1393.560 ;
      RECT 1069.480 0.840 1069.760 1393.560 ;
      RECT 1071.720 0.840 1072.000 1393.560 ;
      RECT 1073.960 0.840 1074.240 1393.560 ;
      RECT 1076.200 0.840 1076.480 1393.560 ;
      RECT 1078.440 0.840 1078.720 1393.560 ;
      RECT 1080.680 0.840 1080.960 1393.560 ;
      RECT 1082.920 0.840 1083.200 1393.560 ;
      RECT 1085.160 0.840 1085.440 1393.560 ;
      RECT 1087.400 0.840 1087.680 1393.560 ;
      RECT 1089.640 0.840 1089.920 1393.560 ;
      RECT 1091.880 0.840 1092.160 1393.560 ;
      RECT 1094.120 0.840 1094.400 1393.560 ;
      RECT 1096.360 0.840 1096.640 1393.560 ;
      RECT 1098.600 0.840 1098.880 1393.560 ;
      RECT 1100.840 0.840 1101.120 1393.560 ;
      RECT 1103.080 0.840 1103.360 1393.560 ;
      RECT 1105.320 0.840 1105.600 1393.560 ;
      RECT 1107.560 0.840 1107.840 1393.560 ;
      RECT 1109.800 0.840 1110.080 1393.560 ;
      RECT 1112.040 0.840 1112.320 1393.560 ;
      RECT 1114.280 0.840 1114.560 1393.560 ;
      RECT 1116.520 0.840 1116.800 1393.560 ;
      RECT 1118.760 0.840 1119.040 1393.560 ;
      RECT 1121.000 0.840 1121.280 1393.560 ;
      RECT 1123.240 0.840 1123.520 1393.560 ;
      RECT 1125.480 0.840 1125.760 1393.560 ;
      RECT 1127.720 0.840 1128.000 1393.560 ;
      RECT 1129.960 0.840 1130.240 1393.560 ;
      RECT 1132.200 0.840 1132.480 1393.560 ;
      RECT 1134.440 0.840 1134.720 1393.560 ;
      RECT 1136.680 0.840 1136.960 1393.560 ;
      RECT 1138.920 0.840 1139.200 1393.560 ;
      RECT 1141.160 0.840 1141.440 1393.560 ;
      RECT 1143.400 0.840 1143.680 1393.560 ;
      RECT 1145.640 0.840 1145.920 1393.560 ;
      RECT 1147.880 0.840 1148.160 1393.560 ;
      RECT 1150.120 0.840 1150.400 1393.560 ;
      RECT 1152.360 0.840 1152.640 1393.560 ;
      RECT 1154.600 0.840 1154.880 1393.560 ;
      RECT 1156.840 0.840 1157.120 1393.560 ;
    END
  END VSS
  PIN VDD
    DIRECTION INOUT ;
    USE POWER ;
    PORT
      LAYER metal4 ;
      RECT 2.120 0.840 2.400 1393.560 ;
      RECT 4.360 0.840 4.640 1393.560 ;
      RECT 6.600 0.840 6.880 1393.560 ;
      RECT 8.840 0.840 9.120 1393.560 ;
      RECT 11.080 0.840 11.360 1393.560 ;
      RECT 13.320 0.840 13.600 1393.560 ;
      RECT 15.560 0.840 15.840 1393.560 ;
      RECT 17.800 0.840 18.080 1393.560 ;
      RECT 20.040 0.840 20.320 1393.560 ;
      RECT 22.280 0.840 22.560 1393.560 ;
      RECT 24.520 0.840 24.800 1393.560 ;
      RECT 26.760 0.840 27.040 1393.560 ;
      RECT 29.000 0.840 29.280 1393.560 ;
      RECT 31.240 0.840 31.520 1393.560 ;
      RECT 33.480 0.840 33.760 1393.560 ;
      RECT 35.720 0.840 36.000 1393.560 ;
      RECT 37.960 0.840 38.240 1393.560 ;
      RECT 40.200 0.840 40.480 1393.560 ;
      RECT 42.440 0.840 42.720 1393.560 ;
      RECT 44.680 0.840 44.960 1393.560 ;
      RECT 46.920 0.840 47.200 1393.560 ;
      RECT 49.160 0.840 49.440 1393.560 ;
      RECT 51.400 0.840 51.680 1393.560 ;
      RECT 53.640 0.840 53.920 1393.560 ;
      RECT 55.880 0.840 56.160 1393.560 ;
      RECT 58.120 0.840 58.400 1393.560 ;
      RECT 60.360 0.840 60.640 1393.560 ;
      RECT 62.600 0.840 62.880 1393.560 ;
      RECT 64.840 0.840 65.120 1393.560 ;
      RECT 67.080 0.840 67.360 1393.560 ;
      RECT 69.320 0.840 69.600 1393.560 ;
      RECT 71.560 0.840 71.840 1393.560 ;
      RECT 73.800 0.840 74.080 1393.560 ;
      RECT 76.040 0.840 76.320 1393.560 ;
      RECT 78.280 0.840 78.560 1393.560 ;
      RECT 80.520 0.840 80.800 1393.560 ;
      RECT 82.760 0.840 83.040 1393.560 ;
      RECT 85.000 0.840 85.280 1393.560 ;
      RECT 87.240 0.840 87.520 1393.560 ;
      RECT 89.480 0.840 89.760 1393.560 ;
      RECT 91.720 0.840 92.000 1393.560 ;
      RECT 93.960 0.840 94.240 1393.560 ;
      RECT 96.200 0.840 96.480 1393.560 ;
      RECT 98.440 0.840 98.720 1393.560 ;
      RECT 100.680 0.840 100.960 1393.560 ;
      RECT 102.920 0.840 103.200 1393.560 ;
      RECT 105.160 0.840 105.440 1393.560 ;
      RECT 107.400 0.840 107.680 1393.560 ;
      RECT 109.640 0.840 109.920 1393.560 ;
      RECT 111.880 0.840 112.160 1393.560 ;
      RECT 114.120 0.840 114.400 1393.560 ;
      RECT 116.360 0.840 116.640 1393.560 ;
      RECT 118.600 0.840 118.880 1393.560 ;
      RECT 120.840 0.840 121.120 1393.560 ;
      RECT 123.080 0.840 123.360 1393.560 ;
      RECT 125.320 0.840 125.600 1393.560 ;
      RECT 127.560 0.840 127.840 1393.560 ;
      RECT 129.800 0.840 130.080 1393.560 ;
      RECT 132.040 0.840 132.320 1393.560 ;
      RECT 134.280 0.840 134.560 1393.560 ;
      RECT 136.520 0.840 136.800 1393.560 ;
      RECT 138.760 0.840 139.040 1393.560 ;
      RECT 141.000 0.840 141.280 1393.560 ;
      RECT 143.240 0.840 143.520 1393.560 ;
      RECT 145.480 0.840 145.760 1393.560 ;
      RECT 147.720 0.840 148.000 1393.560 ;
      RECT 149.960 0.840 150.240 1393.560 ;
      RECT 152.200 0.840 152.480 1393.560 ;
      RECT 154.440 0.840 154.720 1393.560 ;
      RECT 156.680 0.840 156.960 1393.560 ;
      RECT 158.920 0.840 159.200 1393.560 ;
      RECT 161.160 0.840 161.440 1393.560 ;
      RECT 163.400 0.840 163.680 1393.560 ;
      RECT 165.640 0.840 165.920 1393.560 ;
      RECT 167.880 0.840 168.160 1393.560 ;
      RECT 170.120 0.840 170.400 1393.560 ;
      RECT 172.360 0.840 172.640 1393.560 ;
      RECT 174.600 0.840 174.880 1393.560 ;
      RECT 176.840 0.840 177.120 1393.560 ;
      RECT 179.080 0.840 179.360 1393.560 ;
      RECT 181.320 0.840 181.600 1393.560 ;
      RECT 183.560 0.840 183.840 1393.560 ;
      RECT 185.800 0.840 186.080 1393.560 ;
      RECT 188.040 0.840 188.320 1393.560 ;
      RECT 190.280 0.840 190.560 1393.560 ;
      RECT 192.520 0.840 192.800 1393.560 ;
      RECT 194.760 0.840 195.040 1393.560 ;
      RECT 197.000 0.840 197.280 1393.560 ;
      RECT 199.240 0.840 199.520 1393.560 ;
      RECT 201.480 0.840 201.760 1393.560 ;
      RECT 203.720 0.840 204.000 1393.560 ;
      RECT 205.960 0.840 206.240 1393.560 ;
      RECT 208.200 0.840 208.480 1393.560 ;
      RECT 210.440 0.840 210.720 1393.560 ;
      RECT 212.680 0.840 212.960 1393.560 ;
      RECT 214.920 0.840 215.200 1393.560 ;
      RECT 217.160 0.840 217.440 1393.560 ;
      RECT 219.400 0.840 219.680 1393.560 ;
      RECT 221.640 0.840 221.920 1393.560 ;
      RECT 223.880 0.840 224.160 1393.560 ;
      RECT 226.120 0.840 226.400 1393.560 ;
      RECT 228.360 0.840 228.640 1393.560 ;
      RECT 230.600 0.840 230.880 1393.560 ;
      RECT 232.840 0.840 233.120 1393.560 ;
      RECT 235.080 0.840 235.360 1393.560 ;
      RECT 237.320 0.840 237.600 1393.560 ;
      RECT 239.560 0.840 239.840 1393.560 ;
      RECT 241.800 0.840 242.080 1393.560 ;
      RECT 244.040 0.840 244.320 1393.560 ;
      RECT 246.280 0.840 246.560 1393.560 ;
      RECT 248.520 0.840 248.800 1393.560 ;
      RECT 250.760 0.840 251.040 1393.560 ;
      RECT 253.000 0.840 253.280 1393.560 ;
      RECT 255.240 0.840 255.520 1393.560 ;
      RECT 257.480 0.840 257.760 1393.560 ;
      RECT 259.720 0.840 260.000 1393.560 ;
      RECT 261.960 0.840 262.240 1393.560 ;
      RECT 264.200 0.840 264.480 1393.560 ;
      RECT 266.440 0.840 266.720 1393.560 ;
      RECT 268.680 0.840 268.960 1393.560 ;
      RECT 270.920 0.840 271.200 1393.560 ;
      RECT 273.160 0.840 273.440 1393.560 ;
      RECT 275.400 0.840 275.680 1393.560 ;
      RECT 277.640 0.840 277.920 1393.560 ;
      RECT 279.880 0.840 280.160 1393.560 ;
      RECT 282.120 0.840 282.400 1393.560 ;
      RECT 284.360 0.840 284.640 1393.560 ;
      RECT 286.600 0.840 286.880 1393.560 ;
      RECT 288.840 0.840 289.120 1393.560 ;
      RECT 291.080 0.840 291.360 1393.560 ;
      RECT 293.320 0.840 293.600 1393.560 ;
      RECT 295.560 0.840 295.840 1393.560 ;
      RECT 297.800 0.840 298.080 1393.560 ;
      RECT 300.040 0.840 300.320 1393.560 ;
      RECT 302.280 0.840 302.560 1393.560 ;
      RECT 304.520 0.840 304.800 1393.560 ;
      RECT 306.760 0.840 307.040 1393.560 ;
      RECT 309.000 0.840 309.280 1393.560 ;
      RECT 311.240 0.840 311.520 1393.560 ;
      RECT 313.480 0.840 313.760 1393.560 ;
      RECT 315.720 0.840 316.000 1393.560 ;
      RECT 317.960 0.840 318.240 1393.560 ;
      RECT 320.200 0.840 320.480 1393.560 ;
      RECT 322.440 0.840 322.720 1393.560 ;
      RECT 324.680 0.840 324.960 1393.560 ;
      RECT 326.920 0.840 327.200 1393.560 ;
      RECT 329.160 0.840 329.440 1393.560 ;
      RECT 331.400 0.840 331.680 1393.560 ;
      RECT 333.640 0.840 333.920 1393.560 ;
      RECT 335.880 0.840 336.160 1393.560 ;
      RECT 338.120 0.840 338.400 1393.560 ;
      RECT 340.360 0.840 340.640 1393.560 ;
      RECT 342.600 0.840 342.880 1393.560 ;
      RECT 344.840 0.840 345.120 1393.560 ;
      RECT 347.080 0.840 347.360 1393.560 ;
      RECT 349.320 0.840 349.600 1393.560 ;
      RECT 351.560 0.840 351.840 1393.560 ;
      RECT 353.800 0.840 354.080 1393.560 ;
      RECT 356.040 0.840 356.320 1393.560 ;
      RECT 358.280 0.840 358.560 1393.560 ;
      RECT 360.520 0.840 360.800 1393.560 ;
      RECT 362.760 0.840 363.040 1393.560 ;
      RECT 365.000 0.840 365.280 1393.560 ;
      RECT 367.240 0.840 367.520 1393.560 ;
      RECT 369.480 0.840 369.760 1393.560 ;
      RECT 371.720 0.840 372.000 1393.560 ;
      RECT 373.960 0.840 374.240 1393.560 ;
      RECT 376.200 0.840 376.480 1393.560 ;
      RECT 378.440 0.840 378.720 1393.560 ;
      RECT 380.680 0.840 380.960 1393.560 ;
      RECT 382.920 0.840 383.200 1393.560 ;
      RECT 385.160 0.840 385.440 1393.560 ;
      RECT 387.400 0.840 387.680 1393.560 ;
      RECT 389.640 0.840 389.920 1393.560 ;
      RECT 391.880 0.840 392.160 1393.560 ;
      RECT 394.120 0.840 394.400 1393.560 ;
      RECT 396.360 0.840 396.640 1393.560 ;
      RECT 398.600 0.840 398.880 1393.560 ;
      RECT 400.840 0.840 401.120 1393.560 ;
      RECT 403.080 0.840 403.360 1393.560 ;
      RECT 405.320 0.840 405.600 1393.560 ;
      RECT 407.560 0.840 407.840 1393.560 ;
      RECT 409.800 0.840 410.080 1393.560 ;
      RECT 412.040 0.840 412.320 1393.560 ;
      RECT 414.280 0.840 414.560 1393.560 ;
      RECT 416.520 0.840 416.800 1393.560 ;
      RECT 418.760 0.840 419.040 1393.560 ;
      RECT 421.000 0.840 421.280 1393.560 ;
      RECT 423.240 0.840 423.520 1393.560 ;
      RECT 425.480 0.840 425.760 1393.560 ;
      RECT 427.720 0.840 428.000 1393.560 ;
      RECT 429.960 0.840 430.240 1393.560 ;
      RECT 432.200 0.840 432.480 1393.560 ;
      RECT 434.440 0.840 434.720 1393.560 ;
      RECT 436.680 0.840 436.960 1393.560 ;
      RECT 438.920 0.840 439.200 1393.560 ;
      RECT 441.160 0.840 441.440 1393.560 ;
      RECT 443.400 0.840 443.680 1393.560 ;
      RECT 445.640 0.840 445.920 1393.560 ;
      RECT 447.880 0.840 448.160 1393.560 ;
      RECT 450.120 0.840 450.400 1393.560 ;
      RECT 452.360 0.840 452.640 1393.560 ;
      RECT 454.600 0.840 454.880 1393.560 ;
      RECT 456.840 0.840 457.120 1393.560 ;
      RECT 459.080 0.840 459.360 1393.560 ;
      RECT 461.320 0.840 461.600 1393.560 ;
      RECT 463.560 0.840 463.840 1393.560 ;
      RECT 465.800 0.840 466.080 1393.560 ;
      RECT 468.040 0.840 468.320 1393.560 ;
      RECT 470.280 0.840 470.560 1393.560 ;
      RECT 472.520 0.840 472.800 1393.560 ;
      RECT 474.760 0.840 475.040 1393.560 ;
      RECT 477.000 0.840 477.280 1393.560 ;
      RECT 479.240 0.840 479.520 1393.560 ;
      RECT 481.480 0.840 481.760 1393.560 ;
      RECT 483.720 0.840 484.000 1393.560 ;
      RECT 485.960 0.840 486.240 1393.560 ;
      RECT 488.200 0.840 488.480 1393.560 ;
      RECT 490.440 0.840 490.720 1393.560 ;
      RECT 492.680 0.840 492.960 1393.560 ;
      RECT 494.920 0.840 495.200 1393.560 ;
      RECT 497.160 0.840 497.440 1393.560 ;
      RECT 499.400 0.840 499.680 1393.560 ;
      RECT 501.640 0.840 501.920 1393.560 ;
      RECT 503.880 0.840 504.160 1393.560 ;
      RECT 506.120 0.840 506.400 1393.560 ;
      RECT 508.360 0.840 508.640 1393.560 ;
      RECT 510.600 0.840 510.880 1393.560 ;
      RECT 512.840 0.840 513.120 1393.560 ;
      RECT 515.080 0.840 515.360 1393.560 ;
      RECT 517.320 0.840 517.600 1393.560 ;
      RECT 519.560 0.840 519.840 1393.560 ;
      RECT 521.800 0.840 522.080 1393.560 ;
      RECT 524.040 0.840 524.320 1393.560 ;
      RECT 526.280 0.840 526.560 1393.560 ;
      RECT 528.520 0.840 528.800 1393.560 ;
      RECT 530.760 0.840 531.040 1393.560 ;
      RECT 533.000 0.840 533.280 1393.560 ;
      RECT 535.240 0.840 535.520 1393.560 ;
      RECT 537.480 0.840 537.760 1393.560 ;
      RECT 539.720 0.840 540.000 1393.560 ;
      RECT 541.960 0.840 542.240 1393.560 ;
      RECT 544.200 0.840 544.480 1393.560 ;
      RECT 546.440 0.840 546.720 1393.560 ;
      RECT 548.680 0.840 548.960 1393.560 ;
      RECT 550.920 0.840 551.200 1393.560 ;
      RECT 553.160 0.840 553.440 1393.560 ;
      RECT 555.400 0.840 555.680 1393.560 ;
      RECT 557.640 0.840 557.920 1393.560 ;
      RECT 559.880 0.840 560.160 1393.560 ;
      RECT 562.120 0.840 562.400 1393.560 ;
      RECT 564.360 0.840 564.640 1393.560 ;
      RECT 566.600 0.840 566.880 1393.560 ;
      RECT 568.840 0.840 569.120 1393.560 ;
      RECT 571.080 0.840 571.360 1393.560 ;
      RECT 573.320 0.840 573.600 1393.560 ;
      RECT 575.560 0.840 575.840 1393.560 ;
      RECT 577.800 0.840 578.080 1393.560 ;
      RECT 580.040 0.840 580.320 1393.560 ;
      RECT 582.280 0.840 582.560 1393.560 ;
      RECT 584.520 0.840 584.800 1393.560 ;
      RECT 586.760 0.840 587.040 1393.560 ;
      RECT 589.000 0.840 589.280 1393.560 ;
      RECT 591.240 0.840 591.520 1393.560 ;
      RECT 593.480 0.840 593.760 1393.560 ;
      RECT 595.720 0.840 596.000 1393.560 ;
      RECT 597.960 0.840 598.240 1393.560 ;
      RECT 600.200 0.840 600.480 1393.560 ;
      RECT 602.440 0.840 602.720 1393.560 ;
      RECT 604.680 0.840 604.960 1393.560 ;
      RECT 606.920 0.840 607.200 1393.560 ;
      RECT 609.160 0.840 609.440 1393.560 ;
      RECT 611.400 0.840 611.680 1393.560 ;
      RECT 613.640 0.840 613.920 1393.560 ;
      RECT 615.880 0.840 616.160 1393.560 ;
      RECT 618.120 0.840 618.400 1393.560 ;
      RECT 620.360 0.840 620.640 1393.560 ;
      RECT 622.600 0.840 622.880 1393.560 ;
      RECT 624.840 0.840 625.120 1393.560 ;
      RECT 627.080 0.840 627.360 1393.560 ;
      RECT 629.320 0.840 629.600 1393.560 ;
      RECT 631.560 0.840 631.840 1393.560 ;
      RECT 633.800 0.840 634.080 1393.560 ;
      RECT 636.040 0.840 636.320 1393.560 ;
      RECT 638.280 0.840 638.560 1393.560 ;
      RECT 640.520 0.840 640.800 1393.560 ;
      RECT 642.760 0.840 643.040 1393.560 ;
      RECT 645.000 0.840 645.280 1393.560 ;
      RECT 647.240 0.840 647.520 1393.560 ;
      RECT 649.480 0.840 649.760 1393.560 ;
      RECT 651.720 0.840 652.000 1393.560 ;
      RECT 653.960 0.840 654.240 1393.560 ;
      RECT 656.200 0.840 656.480 1393.560 ;
      RECT 658.440 0.840 658.720 1393.560 ;
      RECT 660.680 0.840 660.960 1393.560 ;
      RECT 662.920 0.840 663.200 1393.560 ;
      RECT 665.160 0.840 665.440 1393.560 ;
      RECT 667.400 0.840 667.680 1393.560 ;
      RECT 669.640 0.840 669.920 1393.560 ;
      RECT 671.880 0.840 672.160 1393.560 ;
      RECT 674.120 0.840 674.400 1393.560 ;
      RECT 676.360 0.840 676.640 1393.560 ;
      RECT 678.600 0.840 678.880 1393.560 ;
      RECT 680.840 0.840 681.120 1393.560 ;
      RECT 683.080 0.840 683.360 1393.560 ;
      RECT 685.320 0.840 685.600 1393.560 ;
      RECT 687.560 0.840 687.840 1393.560 ;
      RECT 689.800 0.840 690.080 1393.560 ;
      RECT 692.040 0.840 692.320 1393.560 ;
      RECT 694.280 0.840 694.560 1393.560 ;
      RECT 696.520 0.840 696.800 1393.560 ;
      RECT 698.760 0.840 699.040 1393.560 ;
      RECT 701.000 0.840 701.280 1393.560 ;
      RECT 703.240 0.840 703.520 1393.560 ;
      RECT 705.480 0.840 705.760 1393.560 ;
      RECT 707.720 0.840 708.000 1393.560 ;
      RECT 709.960 0.840 710.240 1393.560 ;
      RECT 712.200 0.840 712.480 1393.560 ;
      RECT 714.440 0.840 714.720 1393.560 ;
      RECT 716.680 0.840 716.960 1393.560 ;
      RECT 718.920 0.840 719.200 1393.560 ;
      RECT 721.160 0.840 721.440 1393.560 ;
      RECT 723.400 0.840 723.680 1393.560 ;
      RECT 725.640 0.840 725.920 1393.560 ;
      RECT 727.880 0.840 728.160 1393.560 ;
      RECT 730.120 0.840 730.400 1393.560 ;
      RECT 732.360 0.840 732.640 1393.560 ;
      RECT 734.600 0.840 734.880 1393.560 ;
      RECT 736.840 0.840 737.120 1393.560 ;
      RECT 739.080 0.840 739.360 1393.560 ;
      RECT 741.320 0.840 741.600 1393.560 ;
      RECT 743.560 0.840 743.840 1393.560 ;
      RECT 745.800 0.840 746.080 1393.560 ;
      RECT 748.040 0.840 748.320 1393.560 ;
      RECT 750.280 0.840 750.560 1393.560 ;
      RECT 752.520 0.840 752.800 1393.560 ;
      RECT 754.760 0.840 755.040 1393.560 ;
      RECT 757.000 0.840 757.280 1393.560 ;
      RECT 759.240 0.840 759.520 1393.560 ;
      RECT 761.480 0.840 761.760 1393.560 ;
      RECT 763.720 0.840 764.000 1393.560 ;
      RECT 765.960 0.840 766.240 1393.560 ;
      RECT 768.200 0.840 768.480 1393.560 ;
      RECT 770.440 0.840 770.720 1393.560 ;
      RECT 772.680 0.840 772.960 1393.560 ;
      RECT 774.920 0.840 775.200 1393.560 ;
      RECT 777.160 0.840 777.440 1393.560 ;
      RECT 779.400 0.840 779.680 1393.560 ;
      RECT 781.640 0.840 781.920 1393.560 ;
      RECT 783.880 0.840 784.160 1393.560 ;
      RECT 786.120 0.840 786.400 1393.560 ;
      RECT 788.360 0.840 788.640 1393.560 ;
      RECT 790.600 0.840 790.880 1393.560 ;
      RECT 792.840 0.840 793.120 1393.560 ;
      RECT 795.080 0.840 795.360 1393.560 ;
      RECT 797.320 0.840 797.600 1393.560 ;
      RECT 799.560 0.840 799.840 1393.560 ;
      RECT 801.800 0.840 802.080 1393.560 ;
      RECT 804.040 0.840 804.320 1393.560 ;
      RECT 806.280 0.840 806.560 1393.560 ;
      RECT 808.520 0.840 808.800 1393.560 ;
      RECT 810.760 0.840 811.040 1393.560 ;
      RECT 813.000 0.840 813.280 1393.560 ;
      RECT 815.240 0.840 815.520 1393.560 ;
      RECT 817.480 0.840 817.760 1393.560 ;
      RECT 819.720 0.840 820.000 1393.560 ;
      RECT 821.960 0.840 822.240 1393.560 ;
      RECT 824.200 0.840 824.480 1393.560 ;
      RECT 826.440 0.840 826.720 1393.560 ;
      RECT 828.680 0.840 828.960 1393.560 ;
      RECT 830.920 0.840 831.200 1393.560 ;
      RECT 833.160 0.840 833.440 1393.560 ;
      RECT 835.400 0.840 835.680 1393.560 ;
      RECT 837.640 0.840 837.920 1393.560 ;
      RECT 839.880 0.840 840.160 1393.560 ;
      RECT 842.120 0.840 842.400 1393.560 ;
      RECT 844.360 0.840 844.640 1393.560 ;
      RECT 846.600 0.840 846.880 1393.560 ;
      RECT 848.840 0.840 849.120 1393.560 ;
      RECT 851.080 0.840 851.360 1393.560 ;
      RECT 853.320 0.840 853.600 1393.560 ;
      RECT 855.560 0.840 855.840 1393.560 ;
      RECT 857.800 0.840 858.080 1393.560 ;
      RECT 860.040 0.840 860.320 1393.560 ;
      RECT 862.280 0.840 862.560 1393.560 ;
      RECT 864.520 0.840 864.800 1393.560 ;
      RECT 866.760 0.840 867.040 1393.560 ;
      RECT 869.000 0.840 869.280 1393.560 ;
      RECT 871.240 0.840 871.520 1393.560 ;
      RECT 873.480 0.840 873.760 1393.560 ;
      RECT 875.720 0.840 876.000 1393.560 ;
      RECT 877.960 0.840 878.240 1393.560 ;
      RECT 880.200 0.840 880.480 1393.560 ;
      RECT 882.440 0.840 882.720 1393.560 ;
      RECT 884.680 0.840 884.960 1393.560 ;
      RECT 886.920 0.840 887.200 1393.560 ;
      RECT 889.160 0.840 889.440 1393.560 ;
      RECT 891.400 0.840 891.680 1393.560 ;
      RECT 893.640 0.840 893.920 1393.560 ;
      RECT 895.880 0.840 896.160 1393.560 ;
      RECT 898.120 0.840 898.400 1393.560 ;
      RECT 900.360 0.840 900.640 1393.560 ;
      RECT 902.600 0.840 902.880 1393.560 ;
      RECT 904.840 0.840 905.120 1393.560 ;
      RECT 907.080 0.840 907.360 1393.560 ;
      RECT 909.320 0.840 909.600 1393.560 ;
      RECT 911.560 0.840 911.840 1393.560 ;
      RECT 913.800 0.840 914.080 1393.560 ;
      RECT 916.040 0.840 916.320 1393.560 ;
      RECT 918.280 0.840 918.560 1393.560 ;
      RECT 920.520 0.840 920.800 1393.560 ;
      RECT 922.760 0.840 923.040 1393.560 ;
      RECT 925.000 0.840 925.280 1393.560 ;
      RECT 927.240 0.840 927.520 1393.560 ;
      RECT 929.480 0.840 929.760 1393.560 ;
      RECT 931.720 0.840 932.000 1393.560 ;
      RECT 933.960 0.840 934.240 1393.560 ;
      RECT 936.200 0.840 936.480 1393.560 ;
      RECT 938.440 0.840 938.720 1393.560 ;
      RECT 940.680 0.840 940.960 1393.560 ;
      RECT 942.920 0.840 943.200 1393.560 ;
      RECT 945.160 0.840 945.440 1393.560 ;
      RECT 947.400 0.840 947.680 1393.560 ;
      RECT 949.640 0.840 949.920 1393.560 ;
      RECT 951.880 0.840 952.160 1393.560 ;
      RECT 954.120 0.840 954.400 1393.560 ;
      RECT 956.360 0.840 956.640 1393.560 ;
      RECT 958.600 0.840 958.880 1393.560 ;
      RECT 960.840 0.840 961.120 1393.560 ;
      RECT 963.080 0.840 963.360 1393.560 ;
      RECT 965.320 0.840 965.600 1393.560 ;
      RECT 967.560 0.840 967.840 1393.560 ;
      RECT 969.800 0.840 970.080 1393.560 ;
      RECT 972.040 0.840 972.320 1393.560 ;
      RECT 974.280 0.840 974.560 1393.560 ;
      RECT 976.520 0.840 976.800 1393.560 ;
      RECT 978.760 0.840 979.040 1393.560 ;
      RECT 981.000 0.840 981.280 1393.560 ;
      RECT 983.240 0.840 983.520 1393.560 ;
      RECT 985.480 0.840 985.760 1393.560 ;
      RECT 987.720 0.840 988.000 1393.560 ;
      RECT 989.960 0.840 990.240 1393.560 ;
      RECT 992.200 0.840 992.480 1393.560 ;
      RECT 994.440 0.840 994.720 1393.560 ;
      RECT 996.680 0.840 996.960 1393.560 ;
      RECT 998.920 0.840 999.200 1393.560 ;
      RECT 1001.160 0.840 1001.440 1393.560 ;
      RECT 1003.400 0.840 1003.680 1393.560 ;
      RECT 1005.640 0.840 1005.920 1393.560 ;
      RECT 1007.880 0.840 1008.160 1393.560 ;
      RECT 1010.120 0.840 1010.400 1393.560 ;
      RECT 1012.360 0.840 1012.640 1393.560 ;
      RECT 1014.600 0.840 1014.880 1393.560 ;
      RECT 1016.840 0.840 1017.120 1393.560 ;
      RECT 1019.080 0.840 1019.360 1393.560 ;
      RECT 1021.320 0.840 1021.600 1393.560 ;
      RECT 1023.560 0.840 1023.840 1393.560 ;
      RECT 1025.800 0.840 1026.080 1393.560 ;
      RECT 1028.040 0.840 1028.320 1393.560 ;
      RECT 1030.280 0.840 1030.560 1393.560 ;
      RECT 1032.520 0.840 1032.800 1393.560 ;
      RECT 1034.760 0.840 1035.040 1393.560 ;
      RECT 1037.000 0.840 1037.280 1393.560 ;
      RECT 1039.240 0.840 1039.520 1393.560 ;
      RECT 1041.480 0.840 1041.760 1393.560 ;
      RECT 1043.720 0.840 1044.000 1393.560 ;
      RECT 1045.960 0.840 1046.240 1393.560 ;
      RECT 1048.200 0.840 1048.480 1393.560 ;
      RECT 1050.440 0.840 1050.720 1393.560 ;
      RECT 1052.680 0.840 1052.960 1393.560 ;
      RECT 1054.920 0.840 1055.200 1393.560 ;
      RECT 1057.160 0.840 1057.440 1393.560 ;
      RECT 1059.400 0.840 1059.680 1393.560 ;
      RECT 1061.640 0.840 1061.920 1393.560 ;
      RECT 1063.880 0.840 1064.160 1393.560 ;
      RECT 1066.120 0.840 1066.400 1393.560 ;
      RECT 1068.360 0.840 1068.640 1393.560 ;
      RECT 1070.600 0.840 1070.880 1393.560 ;
      RECT 1072.840 0.840 1073.120 1393.560 ;
      RECT 1075.080 0.840 1075.360 1393.560 ;
      RECT 1077.320 0.840 1077.600 1393.560 ;
      RECT 1079.560 0.840 1079.840 1393.560 ;
      RECT 1081.800 0.840 1082.080 1393.560 ;
      RECT 1084.040 0.840 1084.320 1393.560 ;
      RECT 1086.280 0.840 1086.560 1393.560 ;
      RECT 1088.520 0.840 1088.800 1393.560 ;
      RECT 1090.760 0.840 1091.040 1393.560 ;
      RECT 1093.000 0.840 1093.280 1393.560 ;
      RECT 1095.240 0.840 1095.520 1393.560 ;
      RECT 1097.480 0.840 1097.760 1393.560 ;
      RECT 1099.720 0.840 1100.000 1393.560 ;
      RECT 1101.960 0.840 1102.240 1393.560 ;
      RECT 1104.200 0.840 1104.480 1393.560 ;
      RECT 1106.440 0.840 1106.720 1393.560 ;
      RECT 1108.680 0.840 1108.960 1393.560 ;
      RECT 1110.920 0.840 1111.200 1393.560 ;
      RECT 1113.160 0.840 1113.440 1393.560 ;
      RECT 1115.400 0.840 1115.680 1393.560 ;
      RECT 1117.640 0.840 1117.920 1393.560 ;
      RECT 1119.880 0.840 1120.160 1393.560 ;
      RECT 1122.120 0.840 1122.400 1393.560 ;
      RECT 1124.360 0.840 1124.640 1393.560 ;
      RECT 1126.600 0.840 1126.880 1393.560 ;
      RECT 1128.840 0.840 1129.120 1393.560 ;
      RECT 1131.080 0.840 1131.360 1393.560 ;
      RECT 1133.320 0.840 1133.600 1393.560 ;
      RECT 1135.560 0.840 1135.840 1393.560 ;
      RECT 1137.800 0.840 1138.080 1393.560 ;
      RECT 1140.040 0.840 1140.320 1393.560 ;
      RECT 1142.280 0.840 1142.560 1393.560 ;
      RECT 1144.520 0.840 1144.800 1393.560 ;
      RECT 1146.760 0.840 1147.040 1393.560 ;
      RECT 1149.000 0.840 1149.280 1393.560 ;
      RECT 1151.240 0.840 1151.520 1393.560 ;
      RECT 1153.480 0.840 1153.760 1393.560 ;
      RECT 1155.720 0.840 1156.000 1393.560 ;
    END
  END VDD
  OBS
    LAYER metal1 ;
    RECT 0 0 1157.670 1394.400 ;
    LAYER metal2 ;
    RECT 0 0 1157.670 1394.400 ;
    LAYER metal3 ;
    RECT 0 0 1157.670 1394.400 ;
    LAYER metal4 ;
    RECT 0 0 1157.670 1394.400 ;
    LAYER OVERLAP ;
    RECT 0 0 1157.670 1394.400 ;
  END
END fakeram_w16_l32768

END LIBRARY
